# CHARACTERIZATION PROVENANCE
# CHAR_STATUS: ESTIMATED_SCALAR
# WARNING: This Liberty file is generated from analytical models,
# NOT from silicon measurement or SPICE post-layout simulation.
# Timing values are estimated from Landau-Khalatnikov transient simulation.
# NOT suitable for signoff or tapeout. Educational/research use only.
# For production characterization, use Cadence Liberate or Synopsys SiliconSmart
# with measured device data.
VERSION 5.8 ;
BUSBITCHARS "[]" ;
DIVIDERCHAR "/" ;

# Minimal layer definition for standalone validation
LAYER met1
  TYPE ROUTING ;
  DIRECTION HORIZONTAL ;
  PITCH 0.46 ;
  WIDTH 0.14 ;
END met1

# Site definition for 1T1R placement
SITE fecim_1t1r_site
  CLASS CORE ;
  SIZE 0.920 BY 4.070 ;
  SYMMETRY X Y ;
END fecim_1t1r_site

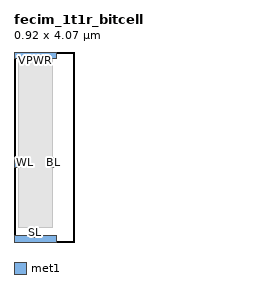
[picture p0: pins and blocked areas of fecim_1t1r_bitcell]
MACRO fecim_1t1r_bitcell
  CLASS CORE ;
  ORIGIN 0 0 ;
  SIZE 0.920 BY 4.070 ;
  SYMMETRY X Y ;
  SITE fecim_1t1r_site ;

  PIN WL
    DIRECTION INPUT ;
    USE SIGNAL ;
    PORT
      LAYER met1 ;
      RECT 0.000 1.600 0.140 1.800 ;
    END
  END WL

  PIN BL
    DIRECTION OUTPUT ;
    USE SIGNAL ;
    PORT
      LAYER met1 ;
      RECT 0.780 1.600 0.920 1.800 ;
    END
  END BL

  PIN SL
    DIRECTION INPUT ;
    USE SIGNAL ;
    PORT
      LAYER met1 ;
      RECT 0.390 0.100 0.530 0.300 ;
    END
  END SL

  PIN VPWR
    DIRECTION INOUT ;
    USE POWER ;
    PORT
      LAYER met1 ;
      RECT 0.000 3.930 0.920 4.070 ;
    END
  END VPWR

  PIN VGND
    DIRECTION INOUT ;
    USE GROUND ;
    PORT
      LAYER met1 ;
      RECT 0.000 0.000 0.920 0.140 ;
    END
  END VGND

  OBS
    LAYER met1 ;
    RECT 0.100 0.300 0.820 3.970 ;
  END

END fecim_1t1r_bitcell

END LIBRARY
